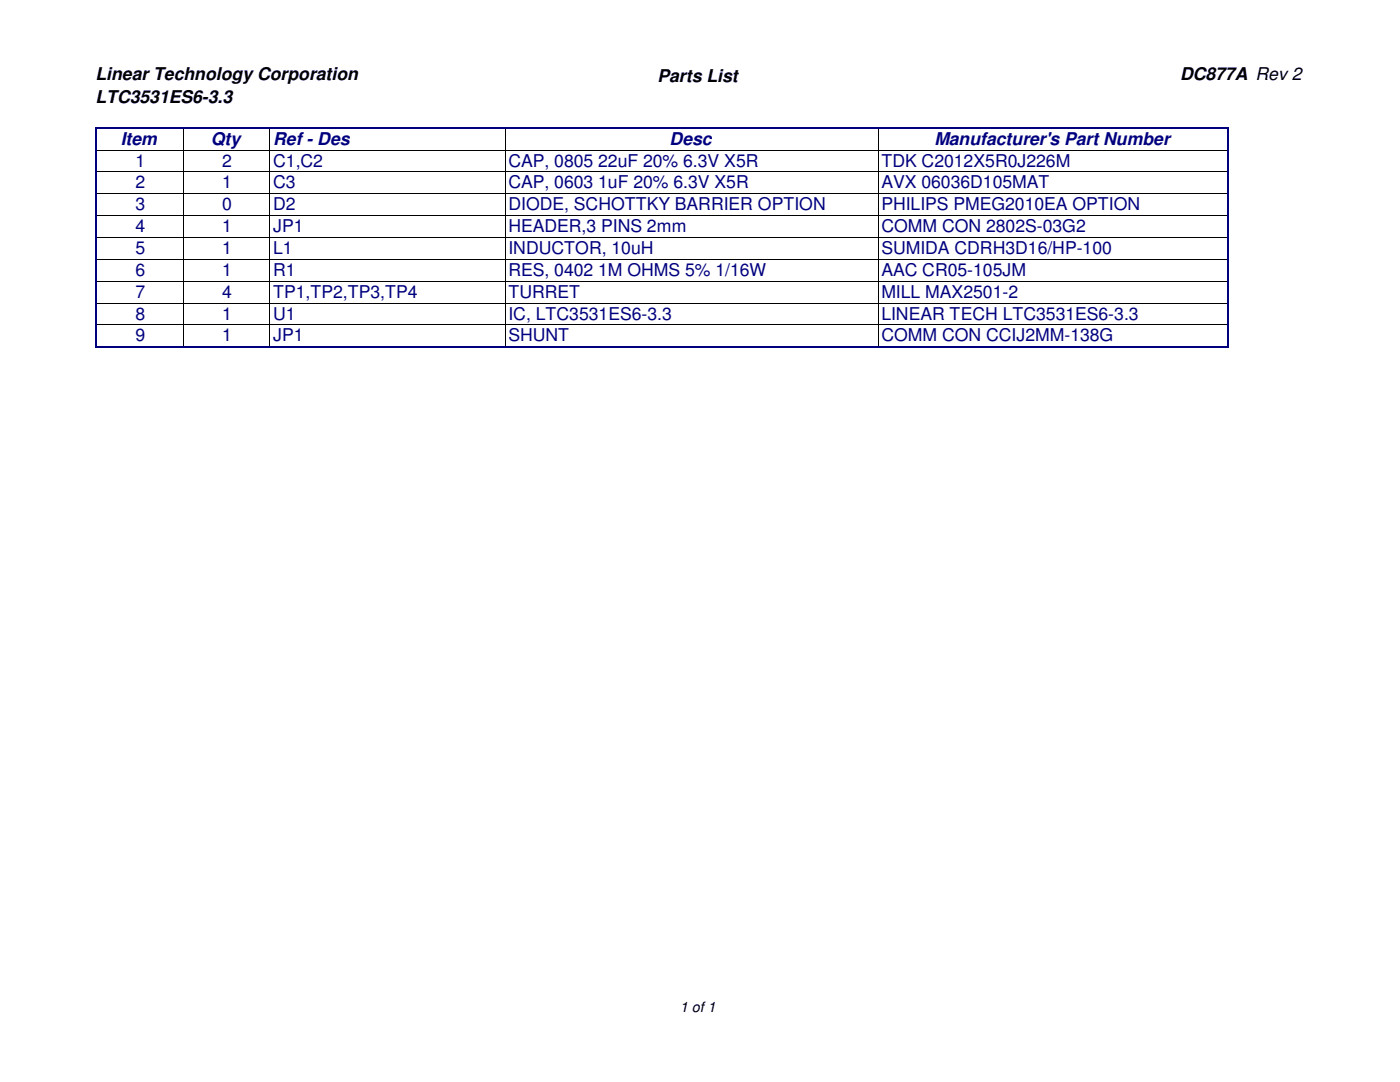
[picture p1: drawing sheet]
<svg xmlns="http://www.w3.org/2000/svg" width="279mm" height="216mm" viewBox="0 0 279 216" stroke-linecap="round" stroke-linejoin="round" font-family="sans-serif">
<defs><g id="words">
<g font-size="3.5">
<text x="19" y="16">Linear Technology Corporation</text>
<text x="131.2" y="16.4">Parts List</text>
<text x="235.5" y="16">DC877A Rev 2</text>
<text x="19" y="20.5">LTC3531ES6-3.3</text>
</g>
<g font-size="3.5" fill="#00007f">
<text x="24.1" y="28.9">Item</text>
<text x="42.1" y="28.9">Qty</text>
<text x="54.5" y="28.9">Ref- Des</text>
<text x="133.6" y="28.9">Desc</text>
<text x="186.5" y="28.9">Manufacturer's Part Number</text>
<text x="27.1" y="33.2">1</text>
<text x="44.4" y="33.2">2</text>
<text x="54.5" y="33.2">C1,C2</text>
<text x="101.5" y="33.2">CAP, 0805</text>
<text x="119.4" y="33.2">22uF 20% 6.3V X5R</text>
<text x="175.9" y="33.2">TDK C2012X5R0J226M</text>
<text x="27.1" y="42">3</text>
<text x="27.1" y="37.6">2</text>
<text x="44.4" y="42">0</text>
<text x="44.4" y="37.6">1</text>
<text x="54.5" y="42">D2</text>
<text x="54.5" y="37.6">C3</text>
<text x="101.5" y="42">DIODE, SCHOTTKY BARRIER OPTION</text>
<text x="101.5" y="37.6">CAP, 0603</text>
<text x="119.4" y="37.6">1uF 20% 6.3V X5R</text>
<text x="175.9" y="42">PHILIPS PMEG2010EA OPTION</text>
<text x="175.9" y="37.6">AVX 06036D105MAT</text>
<text x="27.1" y="46.3">4</text>
<text x="44.4" y="46.3">1</text>
<text x="54.5" y="46.3">JP1</text>
<text x="101.5" y="46.3">HEADER,3 PINS 2mm</text>
<text x="175.9" y="46.3">COMM CON 2802S-03G2</text>
<text x="27.1" y="50.7">5</text>
<text x="44.4" y="50.7">1</text>
<text x="54.5" y="50.7">L1</text>
<text x="101.5" y="50.7">INDUCTOR, 10uH</text>
<text x="175.9" y="50.7">SUMIDA CDRH3D16/HP-100</text>
<text x="27.1" y="59.4">7</text>
<text x="27.1" y="55">6</text>
<text x="44.4" y="59.4">4</text>
<text x="44.4" y="55">1</text>
<text x="54.5" y="59.4">TP1,TP2,TP3,TP4</text>
<text x="54.5" y="55">R1</text>
<text x="101.5" y="59.4">TURRET</text>
<text x="101.5" y="55">RES, 0402</text>
<text x="119.4" y="55">1M OHMS 5% 1/16W</text>
<text x="175.9" y="59.4">MILL MAX2501-2</text>
<text x="175.9" y="55">AAC CR05-105JM</text>
<text x="27.1" y="63.8">8</text>
<text x="44.4" y="63.8">1</text>
<text x="54.5" y="63.8">U1</text>
<text x="101.5" y="63.8">IC, LTC3531ES6-3.3</text>
<text x="175.9" y="63.8">LINEAR TECH LTC3531ES6-3.3</text>
<text x="27.1" y="68.1">9</text>
<text x="44.4" y="68.1">1</text>
<text x="54.5" y="68.1">JP1</text>
<text x="101.5" y="68.1">SHUNT</text>
<text x="175.9" y="68.1">COMM CON CCIJ2MM-138G</text>
</g>
<text font-size="2.8" x="135.7" y="201.9">1 of1</text>
</g></defs>
<g fill="none" stroke="#000" stroke-width=".2">
<path d="M19.4 30h225.7M19.4 34.3h225.7M19.4 38.7h225.7M36.6 25.7v43.5M53.9 25.7v43.5M100.8 25.7v43.5M175.2 25.7v43.5M245.1 25.7v43.5M19.4 43h225.7M19.4 47.4h225.7M19.4 51.8h225.7M19.4 56.1h225.7"/>
<path d="M19.4 60.5h225.7M19.4 64.8h225.7M19.4 69.2h225.7"/>
</g>
<path d="M19 25.6h226.3M19.2 25.4v43.9M245.1 25.4v43.9M19 69.2h226.3" fill="none" stroke="#00007f" stroke-width=".34"/>
<use href="#words"/>
</svg>
